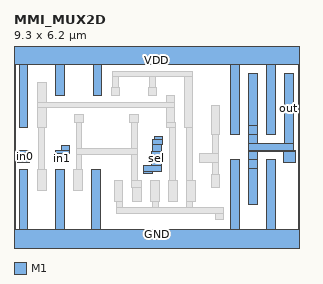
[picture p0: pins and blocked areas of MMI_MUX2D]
MACRO MMI_MUX2D
	CLASS CORE ;
	FOREIGN MMI_MUX2D 0 0 ;
	SIZE 9.3 BY 6.2 ;
	SYMMETRY X Y ;
	SITE CORE1 ;
	PIN out
		DIRECTION output ;
		USE SIGNAL ;
		PORT
			LAYER M1 ;
			RECT 7.655 3.815 7.935 5.485 ;
			LAYER M1 ;
			RECT 7.655 3.5 7.945 3.815 ;
			LAYER M1 ;
			RECT 7.66 3.225 7.945 3.5 ;
			LAYER M1 ;
			RECT 8.835 3.225 9.115 5.485 ;
			LAYER M1 ;
			RECT 7.66 2.98 9.115 3.225 ;
			LAYER M1 ;
			RECT 7.66 2.94 9.18 2.98 ;
			LAYER M1 ;
			RECT 7.66 2.68 7.945 2.94 ;
			LAYER M1 ;
			RECT 7.655 2.395 7.945 2.68 ;
			LAYER M1 ;
			RECT 8.8 2.6 9.18 2.94 ;
			LAYER M1 ;
			RECT 7.655 1.21 7.935 2.395 ;
		END
		AntennaDiffArea 2.393525 ;
	END out
	PIN sel
		DIRECTION input ;
		USE SIGNAL ;
		PORT
			LAYER M1 ;
			RECT 4.58 3.36 4.86 3.45 ;
			LAYER M1 ;
			RECT 4.525 3.17 4.86 3.36 ;
			LAYER M1 ;
			RECT 4.525 2.95 4.8 3.17 ;
			LAYER M1 ;
			RECT 4.49 2.51 4.8 2.95 ;
			LAYER M1 ;
			RECT 4.24 2.315 4.8 2.51 ;
			LAYER M1 ;
			RECT 4.24 2.23 4.52 2.315 ;
		END
		AntennaGateArea 0.927 ;
	END sel
	PIN in1
		DIRECTION input ;
		USE SIGNAL ;
		PORT
			LAYER M1 ;
			RECT 1.535 2.98 1.815 3.16 ;
			LAYER M1 ;
			RECT 1.36 2.88 1.815 2.98 ;
			LAYER M1 ;
			RECT 1.36 2.6 1.74 2.88 ;
		END
		AntennaGateArea 0.693 ;
	END in1
	PIN GND
		DIRECTION inout ;
		USE GROUND ;
		PORT
			LAYER M1 ;
			RECT 0.175 0.42 0.455 2.38 ;
			LAYER M1 ;
			RECT 1.355 0.42 1.635 2.38 ;
			LAYER M1 ;
			RECT 2.535 0.42 2.815 2.38 ;
			LAYER M1 ;
			RECT 7.065 0.42 7.345 2.68 ;
			LAYER M1 ;
			RECT 8.245 0.42 8.525 2.68 ;
			LAYER M1 ;
			RECT 0 -0.42 9.3 0.42 ;
		END
	END GND
	PIN VDD
		DIRECTION inout ;
		USE POWER ;
		PORT
			LAYER M1 ;
			RECT 0 5.78 9.3 6.62 ;
			LAYER M1 ;
			RECT 0.175 3.73 0.455 5.78 ;
			LAYER M1 ;
			RECT 1.355 4.77 1.635 5.78 ;
			LAYER M1 ;
			RECT 2.585 4.77 2.865 5.78 ;
			LAYER M1 ;
			RECT 7.065 3.5 7.345 5.78 ;
			LAYER M1 ;
			RECT 8.245 3.5 8.525 5.78 ;
		END
	END VDD
	PIN in0
		DIRECTION input ;
		USE SIGNAL ;
		PORT
			LAYER M1 ;
			RECT 0.12 2.93 0.5 2.98 ;
			LAYER M1 ;
			RECT 0.12 2.65 0.54 2.93 ;
			LAYER M1 ;
			RECT 0.12 2.6 0.5 2.65 ;
		END
		AntennaGateArea 0.693 ;
	END in0
	OBS
		LAYER M1 ;
		RECT 0.765 4.565 1.045 5.2 ;
		LAYER M1 ;
		RECT 3.21 5.385 5.84 5.58 ;
		LAYER M1 ;
		RECT 3.21 5.05 3.4 5.385 ;
		LAYER M1 ;
		RECT 3.175 4.77 3.455 5.05 ;
		LAYER M1 ;
		RECT 4.415 5.045 4.61 5.385 ;
		LAYER M1 ;
		RECT 4.375 4.765 4.655 5.045 ;
		LAYER M1 ;
		RECT 4.97 4.565 5.25 4.79 ;
		LAYER M1 ;
		RECT 0.765 4.375 5.25 4.565 ;
		LAYER M1 ;
		RECT 0.765 3.73 1.045 4.375 ;
		LAYER M1 ;
		RECT 1.98 3.89 2.26 4.17 ;
		LAYER M1 ;
		RECT 3.775 3.89 4.055 4.17 ;
		LAYER M1 ;
		RECT 4.97 3.9 5.25 4.375 ;
		LAYER M1 ;
		RECT 0.815 2.38 1.005 3.73 ;
		LAYER M1 ;
		RECT 2.025 3.045 2.215 3.89 ;
		LAYER M1 ;
		RECT 3.85 3.045 4.04 3.89 ;
		LAYER M1 ;
		RECT 4.97 3.73 5.255 3.9 ;
		LAYER M1 ;
		RECT 5.56 3.73 5.84 5.385 ;
		LAYER M1 ;
		RECT 2.025 2.855 4.04 3.045 ;
		LAYER M1 ;
		RECT 2.025 2.38 2.215 2.855 ;
		LAYER M1 ;
		RECT 0.765 1.68 1.045 2.38 ;
		LAYER M1 ;
		RECT 1.945 1.68 2.225 2.38 ;
		LAYER M1 ;
		RECT 3.85 2.02 4.04 2.855 ;
		LAYER M1 ;
		RECT 5.06 2.02 5.255 3.73 ;
		LAYER M1 ;
		RECT 5.645 2.02 5.84 3.73 ;
		LAYER M1 ;
		RECT 6.43 3.495 6.71 4.465 ;
		LAYER M1 ;
		RECT 6.475 2.885 6.665 3.495 ;
		LAYER M1 ;
		RECT 6.065 2.88 6.665 2.885 ;
		LAYER M1 ;
		RECT 6.055 2.6 6.665 2.88 ;
		LAYER M1 ;
		RECT 6.475 2.215 6.665 2.6 ;
		LAYER M1 ;
		RECT 3.275 1.32 3.555 2.02 ;
		LAYER M1 ;
		RECT 3.85 1.785 4.145 2.02 ;
		LAYER M1 ;
		RECT 3.865 1.32 4.145 1.785 ;
		LAYER M1 ;
		RECT 4.455 1.32 4.735 2.02 ;
		LAYER M1 ;
		RECT 5.055 1.32 5.335 2.02 ;
		LAYER M1 ;
		RECT 5.645 1.32 5.925 2.02 ;
		LAYER M1 ;
		RECT 6.43 1.765 6.71 2.215 ;
		LAYER M1 ;
		RECT 3.36 1.115 3.55 1.32 ;
		LAYER M1 ;
		RECT 4.51 1.115 4.7 1.32 ;
		LAYER M1 ;
		RECT 5.645 1.115 5.84 1.32 ;
		LAYER M1 ;
		RECT 3.36 0.925 6.845 1.115 ;
		LAYER M1 ;
		RECT 6.565 0.75 6.845 0.925 ;
	END
END MMI_MUX2D
